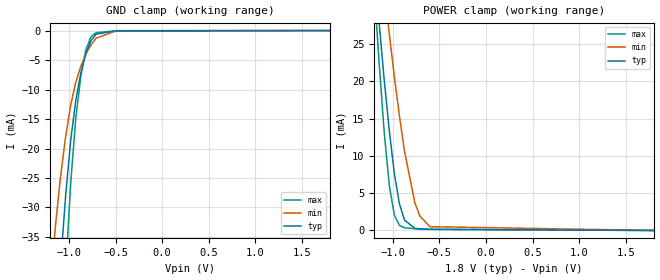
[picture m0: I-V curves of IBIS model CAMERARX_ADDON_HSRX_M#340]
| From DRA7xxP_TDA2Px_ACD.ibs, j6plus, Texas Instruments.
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| Model based on original model for CAMERARX_ADDON
|   Sub model CAMERARX_ADDON_HSRX
[model]   CAMERARX_ADDON_HSRX_M#340
|[Description]  [1.8V-INPUT-X-X]
|   , ,
|[Input Load]
|[Output Drive]
|Voltage   1.8V
|Mode   INPUT
Model_type   Input
Polarity   Non-Inverting
Vinl =  0.07
Vinh =  0.07
C_comp   1.75p   1.5p   2p
[Temperature Range]   25   125   -40
[Voltage Range]   1.8   1.62   1.92
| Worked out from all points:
|   GND clamp passes 1 mA (typ) near -0.73 V on its own axis
|   POWER clamp passes 1 mA (typ) near -0.85 V on its own axis
[GND_clamp]
-1.8V     -259.1mA   -163.8mA   -397mA
-1.145V   -54.02mA   -33.2mA    -82.82mA
-1.091V   -40.07mA   -24.97mA   -60.5mA
-1.036V   -28.12mA   -18.05mA   -41.25mA
-981.8mV  -18.76mA   -12.71mA   -26.08mA
-927.3mV  -11.95mA   -8.839mA   -14.98mA
-872.7mV  -7.206mA   -6.059mA   -7.713mA
-818.2mV  -3.886mA   -3.984mA   -3.248mA
-763.6mV  -1.741mA   -2.414mA   -1.077mA
-709.1mV  -617.6uA   -1.301mA   -355.2uA
-490.9mV  -19.35uA   -29.69uA   -40.89uA
1.8V      90.21nA    775.7nA    1.078uA
[POWER_clamp]
-1.8V     135.7mA    120.7mA    167.8mA
-1.2V     35.92mA    44.99mA    32.8mA
-1.145V   27.84mA    38.58mA    22.4mA
-1.091V   20.23mA    32.35mA    13.19mA
-1.036V   13.36mA    26.34mA    6.062mA
-981.8mV  7.621mA    20.63mA    2.045mA
-927.3mV  3.557mA    15.33mA    682.4uA
-872.7mV  1.39mA     10.6mA     361uA
-763.6mV  294.2uA    3.768mA    236.8uA
-709.1mV  208.6uA    1.943mA    207.5uA
-600mV    147.2uA    508.2uA    161.7uA
1.8V      0A         0A         0A
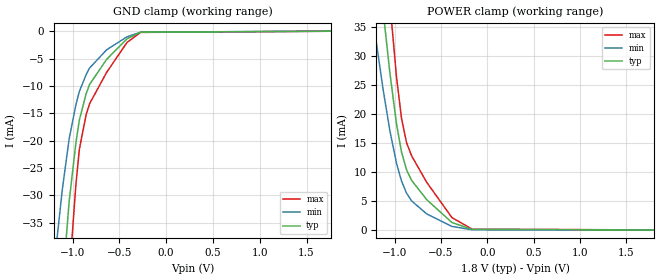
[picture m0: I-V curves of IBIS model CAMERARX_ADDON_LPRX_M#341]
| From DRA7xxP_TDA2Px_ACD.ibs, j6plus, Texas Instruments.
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| Model based on original model for CAMERARX_ADDON
|   Sub model CAMERARX_ADDON_LPRX
[model]   CAMERARX_ADDON_LPRX_M#341
|[Description]  [1.8V-INPUT-X-X]
|   , ,
|[Input Load]
|[Output Drive]
|Voltage   1.8V
|Mode   INPUT
Model_type   Input
Polarity   Non-Inverting
Vinl =  0.654
Vinh =  0.749
C_comp   1.75p   1.5p   2p
[Model Spec]
Vinl   0.654   0.586   0.722
Vinh   0.749   0.675   0.822
[Temperature Range]   25   125   -40
[Voltage Range]   1.8   1.62   1.92
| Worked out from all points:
|   GND clamp passes 1 mA (typ) near -0.39 V on its own axis
|   POWER clamp passes 1 mA (typ) near -0.35 V on its own axis
[POWER_clamp]
-1.8V     156.8mA    109.4mA    217.7mA
-1.255V   58.58mA    38.5mA     83.58mA
-1.127V   37.93mA    24.29mA    54.73mA
-1.055V   27.33mA    17.27mA    39.59mA
-981.8mV  18.3mA     11.5mA     26.4mA
-927.3mV  13.42mA    8.419mA    19.22mA
-872.7mV  10.36mA    6.348mA    15.04mA
-818.2mV  8.551mA    5.012mA    12.79mA
-654.5mV  5.218mA    2.76mA     8.209mA
-381.8mV  1.281mA    612uA      2.13mA
-163.6mV  106uA      34.63uA    142.1uA
1.8V      2.655uA    1.447uA    5.48uA
[GND_clamp]
-1.8V     -252.1mA   -161mA     -379.9mA
-1.218V   -74.99mA   -46.16mA   -113.7mA
-1.109V   -46.67mA   -28.87mA   -69.57mA
-1.036V   -31.06mA   -19.64mA   -44.89mA
-963.6mV  -20.33mA   -13.39mA   -27.93mA
-927.3mV  -16.23mA   -11mA      -21.58mA
-854.5mV  -11.42mA   -7.916mA   -15.25mA
-818.2mV  -9.733mA   -6.736mA   -13.26mA
-636.4mV  -5.156mA   -3.402mA   -7.535mA
-418.2mV  -1.379mA   -1.021mA   -2.048mA
-272.7mV  -182.6uA   -178.1uA   -212.2uA
1.764V    1.345uA    26.47uA    2.07uA
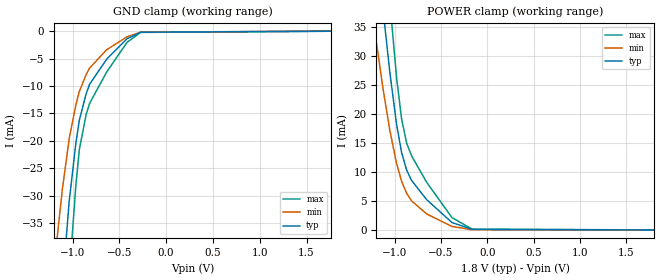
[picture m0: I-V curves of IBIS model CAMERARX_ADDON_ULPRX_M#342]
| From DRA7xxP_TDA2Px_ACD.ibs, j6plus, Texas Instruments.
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| Model based on original model for CAMERARX_ADDON
|   Sub model CAMERARX_ADDON_ULPRX
[model]   CAMERARX_ADDON_ULPRX_M#342
|[Description]  [1.8V-INPUT-X-X]
|   , ,
|[Input Load]
|[Output Drive]
|Voltage   1.8V
|Mode   INPUT
Model_type   Input
Polarity   Non-Inverting
Vinl =  0.5
Vinh =  0.61
C_comp   1.75p   1.5p   2p
[Model Spec]
Vinl   0.5   0.342   0.66
Vinh   0.61   0.382   0.838
[Temperature Range]   25   125   -40
[Voltage Range]   1.8   1.62   1.92
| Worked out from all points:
|   GND clamp passes 1 mA (typ) near -0.39 V on its own axis
|   POWER clamp passes 1 mA (typ) near -0.35 V on its own axis
[POWER_clamp]
-1.8V     156.8mA    109.4mA    217.6mA
-1.255V   58.56mA    38.5mA     83.54mA
-1.127V   37.9mA     24.28mA    54.68mA
-1.055V   27.3mA     17.26mA    39.54mA
-981.8mV  18.27mA    11.49mA    26.35mA
-927.3mV  13.39mA    8.411mA    19.17mA
-872.7mV  10.33mA    6.34mA     15mA
-818.2mV  8.522mA    5.003mA    12.75mA
-654.5mV  5.201mA    2.752mA    8.19mA
-381.8mV  1.28mA     611uA      2.13mA
-163.6mV  106uA      34.6uA     142.1uA
1.8V      2.655uA    1.447uA    5.481uA
[GND_clamp]
-1.8V     -252.1mA   -161mA     -379.9mA
-1.218V   -74.98mA   -46.16mA   -113.7mA
-1.109V   -46.66mA   -28.87mA   -69.55mA
-1.036V   -31.05mA   -19.64mA   -44.87mA
-963.6mV  -20.31mA   -13.39mA   -27.9mA
-927.3mV  -16.22mA   -10.99mA   -21.55mA
-854.5mV  -11.4mA    -7.912mA   -15.2mA
-818.2mV  -9.705mA   -6.732mA   -13.19mA
-636.4mV  -5.121mA   -3.393mA   -7.475mA
-418.2mV  -1.376mA   -1.02mA    -2.041mA
-272.7mV  -182.5uA   -178uA     -212uA
1.764V    1.345uA    26.46uA    2.07uA
